VERSION 5.7 ;
  NOWIREEXTENSIONATPIN ON ;
  DIVIDERCHAR "/" ;
  BUSBITCHARS "[]" ;
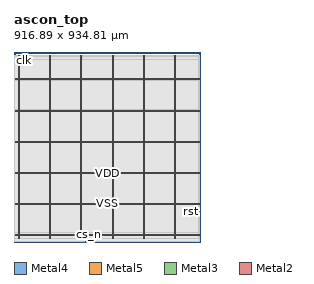
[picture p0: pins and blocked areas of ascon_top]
MACRO ascon_top
  CLASS BLOCK ;
  FOREIGN ascon_top ;
  ORIGIN 0.000 0.000 ;
  SIZE 916.890 BY 934.810 ;
  PIN VDD
    DIRECTION INOUT ;
    USE POWER ;
    PORT
      LAYER Metal4 ;
        RECT 22.240 15.380 23.840 917.580 ;
    END
    PORT
      LAYER Metal4 ;
        RECT 175.840 15.380 177.440 917.580 ;
    END
    PORT
      LAYER Metal4 ;
        RECT 329.440 15.380 331.040 917.580 ;
    END
    PORT
      LAYER Metal4 ;
        RECT 483.040 15.380 484.640 917.580 ;
    END
    PORT
      LAYER Metal4 ;
        RECT 636.640 15.380 638.240 917.580 ;
    END
    PORT
      LAYER Metal4 ;
        RECT 790.240 15.380 791.840 917.580 ;
    END
    PORT
      LAYER Metal5 ;
        RECT 6.420 31.530 910.300 33.130 ;
    END
    PORT
      LAYER Metal5 ;
        RECT 6.420 184.710 910.300 186.310 ;
    END
    PORT
      LAYER Metal5 ;
        RECT 6.420 337.890 910.300 339.490 ;
    END
    PORT
      LAYER Metal5 ;
        RECT 6.420 491.070 910.300 492.670 ;
    END
    PORT
      LAYER Metal5 ;
        RECT 6.420 644.250 910.300 645.850 ;
    END
    PORT
      LAYER Metal5 ;
        RECT 6.420 797.430 910.300 799.030 ;
    END
  END VDD
  PIN VSS
    DIRECTION INOUT ;
    USE GROUND ;
    PORT
      LAYER Metal4 ;
        RECT 25.540 15.380 27.140 917.580 ;
    END
    PORT
      LAYER Metal4 ;
        RECT 179.140 15.380 180.740 917.580 ;
    END
    PORT
      LAYER Metal4 ;
        RECT 332.740 15.380 334.340 917.580 ;
    END
    PORT
      LAYER Metal4 ;
        RECT 486.340 15.380 487.940 917.580 ;
    END
    PORT
      LAYER Metal4 ;
        RECT 639.940 15.380 641.540 917.580 ;
    END
    PORT
      LAYER Metal4 ;
        RECT 793.540 15.380 795.140 917.580 ;
    END
    PORT
      LAYER Metal5 ;
        RECT 6.420 34.830 910.300 36.430 ;
    END
    PORT
      LAYER Metal5 ;
        RECT 6.420 188.010 910.300 189.610 ;
    END
    PORT
      LAYER Metal5 ;
        RECT 6.420 341.190 910.300 342.790 ;
    END
    PORT
      LAYER Metal5 ;
        RECT 6.420 494.370 910.300 495.970 ;
    END
    PORT
      LAYER Metal5 ;
        RECT 6.420 647.550 910.300 649.150 ;
    END
    PORT
      LAYER Metal5 ;
        RECT 6.420 800.730 910.300 802.330 ;
    END
  END VSS
  PIN clk
    DIRECTION INPUT ;
    USE SIGNAL ;
    ANTENNAGATEAREA 4.738000 ;
    PORT
      LAYER Metal3 ;
        RECT 0.000 897.120 4.000 897.680 ;
    END
  END clk
  PIN cs_n
    DIRECTION INPUT ;
    USE SIGNAL ;
    ANTENNAGATEAREA 0.498500 ;
    PORT
      LAYER Metal2 ;
        RECT 369.600 0.000 370.160 4.000 ;
    END
  END cs_n
  PIN miso
    DIRECTION OUTPUT ;
    USE SIGNAL ;
    ANTENNADIFFAREA 1.986000 ;
    PORT
      LAYER Metal2 ;
        RECT 379.680 0.000 380.240 4.000 ;
    END
  END miso
  PIN mosi
    DIRECTION INPUT ;
    USE SIGNAL ;
    ANTENNAGATEAREA 0.741000 ;
    PORT
      LAYER Metal2 ;
        RECT 372.960 0.000 373.520 4.000 ;
    END
  END mosi
  PIN rst
    DIRECTION INPUT ;
    USE SIGNAL ;
    ANTENNAGATEAREA 0.498500 ;
    PORT
      LAYER Metal3 ;
        RECT 912.890 147.840 916.890 148.400 ;
    END
  END rst
  PIN sclk
    DIRECTION INPUT ;
    USE SIGNAL ;
    ANTENNAGATEAREA 0.741000 ;
    PORT
      LAYER Metal2 ;
        RECT 352.800 0.000 353.360 4.000 ;
    END
  END sclk
  OBS
      LAYER Nwell ;
        RECT 6.290 15.250 910.430 917.710 ;
      LAYER Metal1 ;
        RECT 6.720 15.380 910.000 917.580 ;
      LAYER Metal2 ;
        RECT 8.540 4.300 908.740 917.700 ;
        RECT 8.540 4.000 352.500 4.300 ;
        RECT 353.660 4.000 369.300 4.300 ;
        RECT 370.460 4.000 372.660 4.300 ;
        RECT 373.820 4.000 379.380 4.300 ;
        RECT 380.540 4.000 908.740 4.300 ;
      LAYER Metal3 ;
        RECT 0.090 897.980 912.890 917.420 ;
        RECT 4.300 896.820 912.890 897.980 ;
        RECT 0.090 148.700 912.890 896.820 ;
        RECT 0.090 147.540 912.590 148.700 ;
        RECT 0.090 4.060 912.890 147.540 ;
      LAYER Metal4 ;
        RECT 0.140 16.890 21.940 911.590 ;
        RECT 24.140 16.890 25.240 911.590 ;
        RECT 27.440 16.890 175.540 911.590 ;
        RECT 177.740 16.890 178.840 911.590 ;
        RECT 181.040 16.890 329.140 911.590 ;
        RECT 331.340 16.890 332.440 911.590 ;
        RECT 334.640 16.890 482.740 911.590 ;
        RECT 484.940 16.890 486.040 911.590 ;
        RECT 488.240 16.890 636.340 911.590 ;
        RECT 638.540 16.890 639.640 911.590 ;
        RECT 641.840 16.890 789.940 911.590 ;
        RECT 792.140 16.890 793.240 911.590 ;
        RECT 795.440 16.890 906.500 911.590 ;
      LAYER Metal5 ;
        RECT 0.060 802.830 906.580 896.170 ;
        RECT 0.060 800.230 5.920 802.830 ;
        RECT 0.060 799.530 906.580 800.230 ;
        RECT 0.060 796.930 5.920 799.530 ;
        RECT 0.060 649.650 906.580 796.930 ;
        RECT 0.060 647.050 5.920 649.650 ;
        RECT 0.060 646.350 906.580 647.050 ;
        RECT 0.060 643.750 5.920 646.350 ;
        RECT 0.060 496.470 906.580 643.750 ;
        RECT 0.060 493.870 5.920 496.470 ;
        RECT 0.060 493.170 906.580 493.870 ;
        RECT 0.060 490.570 5.920 493.170 ;
        RECT 0.060 343.290 906.580 490.570 ;
        RECT 0.060 340.690 5.920 343.290 ;
        RECT 0.060 339.990 906.580 340.690 ;
        RECT 0.060 337.390 5.920 339.990 ;
        RECT 0.060 190.110 906.580 337.390 ;
        RECT 0.060 187.510 5.920 190.110 ;
        RECT 0.060 186.810 906.580 187.510 ;
        RECT 0.060 184.210 5.920 186.810 ;
        RECT 0.060 45.230 906.580 184.210 ;
  END
END ascon_top
END LIBRARY

